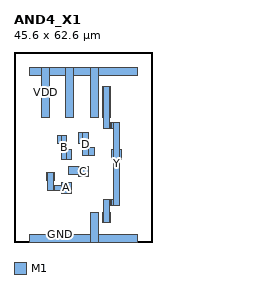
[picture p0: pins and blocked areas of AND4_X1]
MACRO AND4_X1
  CLASS CORE ;
  ORIGIN 0 0 ;
  SIZE 45.600 BY 62.600 ;
  SYMMETRY X Y ;
  SITE TR1um_site ;
  PIN VDD
    DIRECTION INOUT ;
    USE POWER ;
    PORT
      LAYER M1 ;
        RECT 5.000 55.000 9.100 57.600 ;
      LAYER M1 ;
        RECT 9.100 41.000 11.700 57.600 ;
      LAYER M1 ;
        RECT 11.700 55.000 17.100 57.600 ;
      LAYER M1 ;
        RECT 17.100 41.000 19.700 57.600 ;
      LAYER M1 ;
        RECT 19.700 55.000 25.100 57.600 ;
      LAYER M1 ;
        RECT 25.100 41.000 27.700 57.600 ;
      LAYER M1 ;
        RECT 27.700 55.000 40.600 57.600 ;
    END
  END VDD
  PIN GND
    DIRECTION INOUT ;
    USE GROUND ;
    PORT
      LAYER M1 ;
        RECT 5.000 0.000 25.100 2.600 ;
      LAYER M1 ;
        RECT 25.100 0.000 27.700 9.800 ;
      LAYER M1 ;
        RECT 27.700 0.000 40.600 2.600 ;
    END
  END GND
  PIN Y
    DIRECTION OUTPUT ;
    USE SIGNAL ;
    PORT
      LAYER M1 ;
        RECT 29.100 6.400 29.500 9.800 ;
      LAYER M1 ;
        RECT 29.100 41.000 29.500 51.200 ;
      LAYER M1 ;
        RECT 29.500 6.400 31.300 13.900 ;
      LAYER M1 ;
        RECT 29.500 37.500 31.300 51.200 ;
      LAYER M1 ;
        RECT 31.300 6.400 31.700 9.800 ;
      LAYER M1 ;
        RECT 31.300 12.100 31.700 13.900 ;
      LAYER M1 ;
        RECT 31.300 37.500 31.700 39.300 ;
      LAYER M1 ;
        RECT 31.300 41.000 31.700 51.200 ;
      LAYER M1 ;
        RECT 31.700 12.100 32.100 13.900 ;
      LAYER M1 ;
        RECT 31.700 37.500 32.100 39.300 ;
      LAYER M1 ;
        RECT 32.100 12.100 32.900 13.900 ;
      LAYER M1 ;
        RECT 32.100 27.100 32.900 30.500 ;
      LAYER M1 ;
        RECT 32.100 37.500 32.900 39.300 ;
      LAYER M1 ;
        RECT 32.900 12.100 34.700 39.300 ;
      LAYER M1 ;
        RECT 34.700 27.100 35.500 30.500 ;
    END
  END Y
  PIN A
    DIRECTION INPUT ;
    USE SIGNAL ;
    PORT
      LAYER M1 ;
        RECT 10.600 20.400 11.100 23.000 ;
      LAYER M1 ;
        RECT 11.100 16.900 12.900 23.000 ;
      LAYER M1 ;
        RECT 12.900 16.900 13.200 18.700 ;
      LAYER M1 ;
        RECT 12.900 20.400 13.200 23.000 ;
      LAYER M1 ;
        RECT 13.200 16.900 15.600 18.700 ;
      LAYER M1 ;
        RECT 15.600 16.100 19.000 19.500 ;
    END
  END A
  PIN B
    DIRECTION INPUT ;
    USE SIGNAL ;
    PORT
      LAYER M1 ;
        RECT 14.400 32.600 15.600 35.200 ;
      LAYER M1 ;
        RECT 15.600 27.100 17.400 35.200 ;
      LAYER M1 ;
        RECT 17.400 27.100 19.000 30.500 ;
    END
  END B
  PIN C
    DIRECTION INPUT ;
    USE SIGNAL ;
    PORT
      LAYER M1 ;
        RECT 17.900 22.400 21.100 25.000 ;
      LAYER M1 ;
        RECT 21.100 21.600 24.500 25.000 ;
    END
  END C
  PIN D
    DIRECTION INPUT ;
    USE SIGNAL ;
    PORT
      LAYER M1 ;
        RECT 21.100 32.600 22.700 36.000 ;
      LAYER M1 ;
        RECT 22.700 28.400 24.500 36.000 ;
      LAYER M1 ;
        RECT 24.500 28.400 26.400 31.000 ;
    END
  END D
END AND4_X1
